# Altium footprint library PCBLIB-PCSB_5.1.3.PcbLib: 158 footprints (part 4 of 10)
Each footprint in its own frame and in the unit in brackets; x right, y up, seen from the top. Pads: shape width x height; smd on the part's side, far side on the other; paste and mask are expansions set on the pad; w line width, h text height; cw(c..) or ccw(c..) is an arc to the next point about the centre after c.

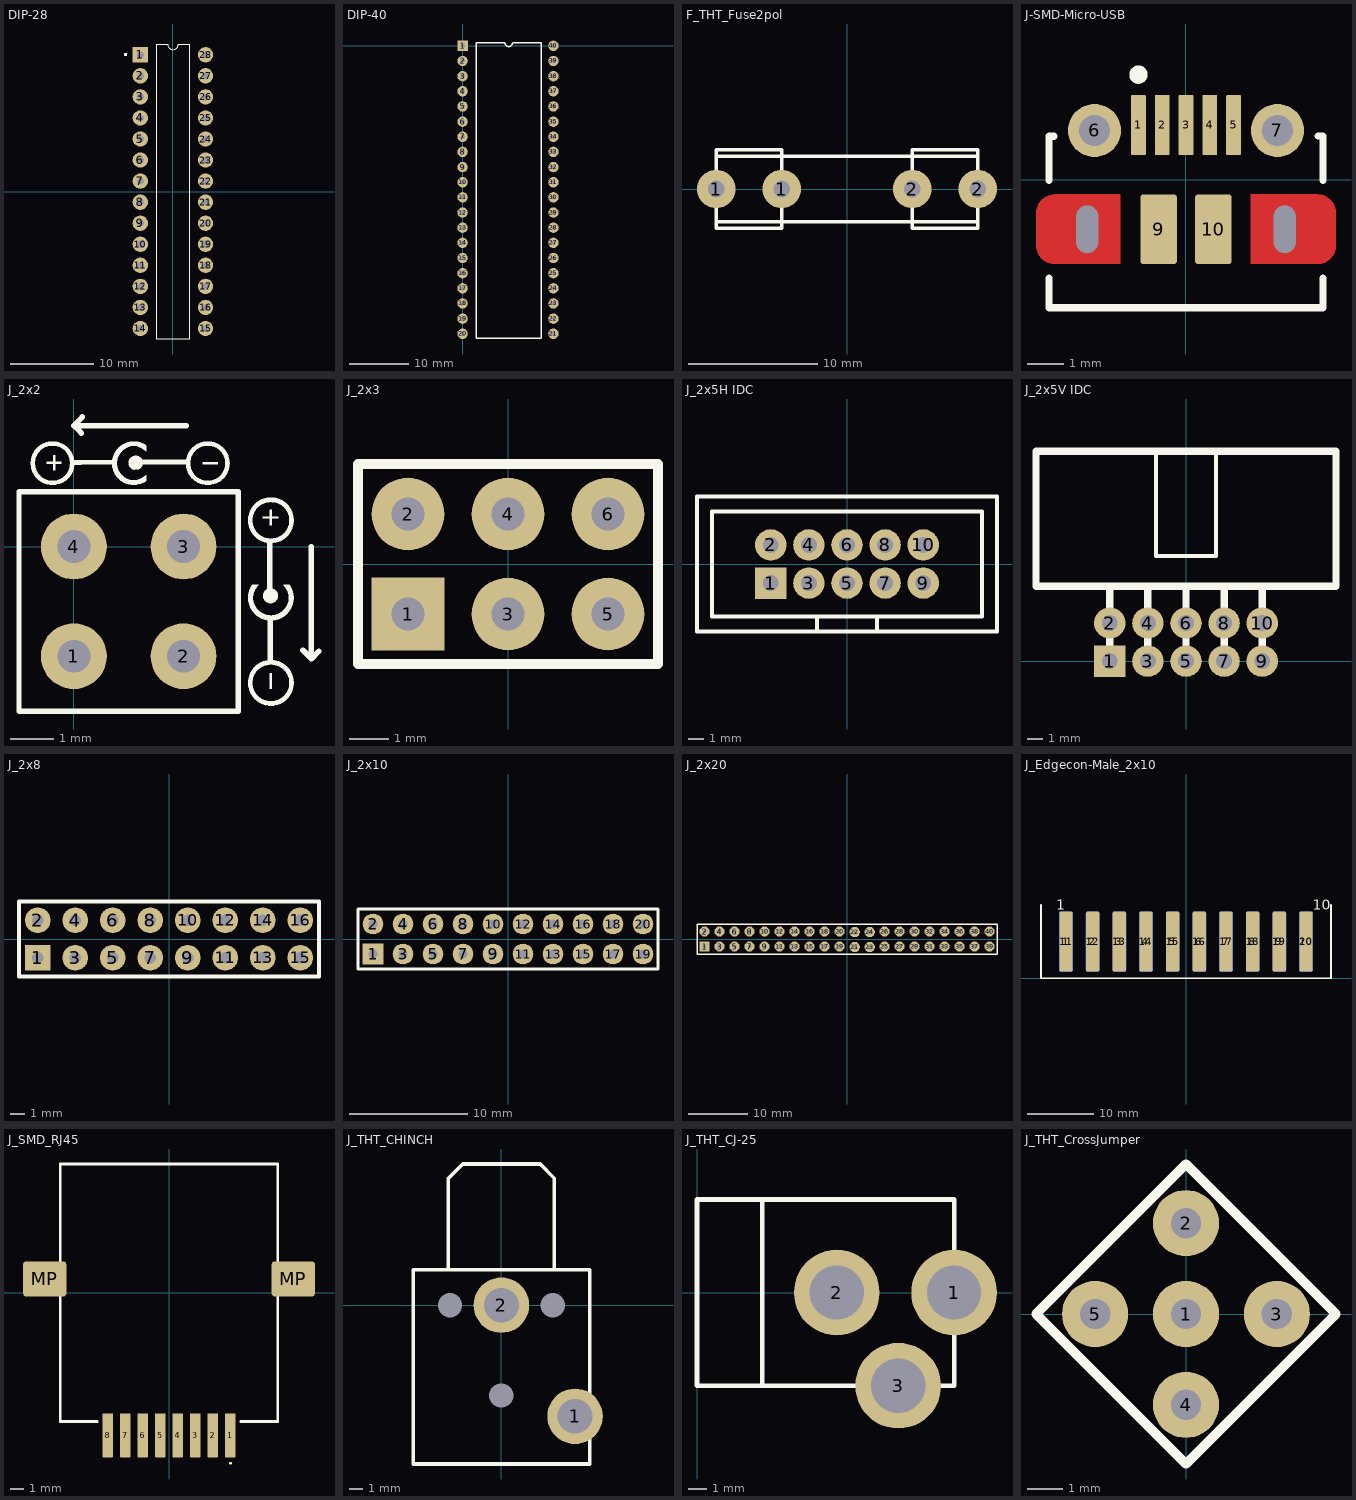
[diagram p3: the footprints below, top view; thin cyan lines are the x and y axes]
## DIP-28 [mm] "LB-2024-04-17"
pads (28):
  rect 1.85x1.85 hole 0.85: 1(-3.935,16.51)
  round 1.85 hole 0.85: 2(-3.935,13.97) 3(-3.935,11.43) 4(-3.935,8.89) 5(-3.935,6.35) 6(-3.935,3.81) 7(-3.935,1.27) 8(-3.935,-1.27) 9(-3.935,-3.81) 10(-3.935,-6.35) 11(-3.935,-8.89) 12(-3.935,-11.43) 13(-3.935,-13.97) 14(-3.935,-16.51) 15(3.935,-16.51) 16(3.935,-13.97) 17(3.935,-11.43) 18(3.935,-8.89) 19(3.935,-6.35) 20(3.935,-3.81) 21(3.935,-1.27) 22(3.935,1.27) 23(3.935,3.81) 24(3.935,6.35) 25(3.935,8.89) 26(3.935,11.43) 27(3.935,13.97) 28(3.935,16.51)
Top Overlay:
  circle w0.2: c-5.714,16.544 r0.1
  lines w0.14: -0.66,17.78 -1,17.78 -2,17.78 -2,-17.78 2,-17.78 2,17.78 ; -0.635,17.78 ccw(c0,17.78) 0.635,17.78 ; 0.642,17.78 1.642,17.78 1.981,17.78
Mechanical 13:
  circle w0.2: c-5.714,16.544 r0.1

## DIP-40 [mm] "LB-2024-04-17"
pads (40):
  rect 1.75x1.75 hole 0.75: 1(0,0)
  round 1.75 hole 0.75: 2(0,-2.54) 3(0,-5.08) 4(0,-7.62) 5(0,-10.16) 6(0,-12.7) 7(0,-15.24) 8(0,-17.78) 9(0,-20.32) 10(0,-22.86) 11(0,-25.4) 12(0,-27.94) 13(0,-30.48) 14(0,-33.02) 15(0,-35.56) 16(0,-38.1) 17(0,-40.64) 18(0,-43.18) 19(0,-45.72) 20(0,-48.26) 21(15.24,-48.26) 22(15.24,-45.72) 23(15.24,-43.18) 24(15.24,-40.64) 25(15.24,-38.1) 26(15.24,-35.56) 27(15.24,-33.02) 28(15.24,-30.48) 29(15.24,-27.94) 30(15.24,-25.4) 31(15.24,-22.86) 32(15.24,-20.32) 33(15.24,-17.78) 34(15.24,-15.24) 35(15.24,-12.7) 36(15.24,-10.16) 37(15.24,-7.62) 38(15.24,-5.08) 39(15.24,-2.54) 40(15.24,0)
Top Overlay:
  lines w0.254: 2.286,-49.022 13.208,-49.022 13.208,0.508 8.382,0.508 cw(c7.747,0.508) 7.112,0.508 2.286,0.508 2.286,-49.022

## F_THT_Fuse2pol [mm] "LB-2024-04-17"
pads (4):
  round 3 hole 1.3: 1(-10.163,0.008) 1(-5.083,0.008) 2(5.077,0.008) 2(10.157,0.008)
Top Overlay:
  lines w0.254: -10.163,-2.532 -10.163,-3.04 -5.083,-3.04 -5.083,-2.532 -5.083,2.548 -5.083,3.056 -10.163,3.056 -10.163,2.548 ; -10.163,-2.532 10.157,-2.532 ; -10.163,-2.532 -10.163,2.548 ; -10.163,2.548 10.157,2.548 ; 10.157,-2.532 10.157,-3.04 5.077,-3.04 5.077,-2.532 5.077,2.548 5.077,3.056 10.157,3.056 10.157,2.548 ; 10.157,-2.532 10.157,2.548

## J-SMD-Micro-USB [mm] "LB-2024-04-18"
height 2.673
pads (11):
  rrect15% 0.4x1.65 smd paste-0.02 mask+0.05: 1(-1.3,1.5) 2(-0.65,1.5) 3(0,1.5) 4(0.65,1.5) 5(1.3,1.5)
  round 1.45 hole 0.85: 6(-2.5,1.35) 7(2.5,1.35)
  rrect50% 0x0 hole 0.6 slot 1.3 at 90 deg: 8(-2.7,-1.35) 11(2.7,-1.35)
  rrect15% 1x1.9 smd paste-0.02 mask+0.05: 9(-0.75,-1.35) 10(0.75,-1.35)
Top Layer:
  circle w0.5: c-3.6,-1.8 r0.25
  circle w0.5: c-3.6,-0.9 r0.25
  circle w0.5: c3.6,-1.8 r0.25
  circle w0.5: c3.6,-0.9 r0.25
  region: -1.8,-2.3 -1.8,-0.4 -3.6,-0.4 -3.6,-2.3
  region: -3.6,-1.8 -3.6,-0.9 -4.1,-0.9 -4.1,-1.8
  region: 1.775,-0.4 1.775,-2.3 3.6,-2.3 3.6,-0.4
  region: 3.6,-0.9 3.6,-1.8 4.1,-1.8 4.1,-0.9
Top Overlay:
  circle w0.25: c-1.3,2.875 r0.125
  lines w0.2: -3.745,-2.688 -3.745,-3.5 3.745,-3.5 3.745,-2.688 ; -3.745,-0.012 -3.745,1.195 -3.614,1.195 ; 3.615,1.2 3.745,1.2 3.745,-0.012

## J_2x2 [mil] "LB-2024-05-28"
pads (4):
  round 60 hole 30: 1(0,-100) 2(100,-100) 3(100,0) 4(0,0)
Top Overlay:
  drawing of 20 lines, arcs and shapes, not listed

## J_2x3 [mm] "LB-2024-04-19"
pads (6):
  rect 1.85x1.85 hole 0.85 mask+0.102: 1(-2.54,-1.27)
  round 1.85 hole 0.85 mask+0.102: 2(-2.54,1.27) 3(0,-1.27) 4(0,1.27) 5(2.54,-1.27) 6(2.54,1.27)
Top Overlay:
  lines w0.254: -3.81,-2.54 -3.81,2.54 3.81,2.54 3.81,-2.54 -3.81,-2.54

## J_2x5H IDC [mm] "LB-2024-04-19"
height 9
pads (10):
  rect 2.1x2.1 hole 1.05 mask+0.102: 1(-5.08,-1.27)
  round 2.1 hole 1.05 mask+0.102: 2(-5.08,1.27) 3(-2.54,-1.27) 4(-2.54,1.27) 5(0,-1.27) 6(0,1.27) 7(2.54,-1.27) 8(2.54,1.27) 9(5.08,-1.27) 10(5.08,1.27)
Top Overlay:
  lines w0.254: -2,-4.5 -2,-3.5 ; -0.5,4.5 10,4.5 10,-4.5 -10,-4.5 -10,4.5 0,4.5 ; 2,-4.5 2,-3.5 ; -9,-3.5 -9,3.5 9,3.5 9,-3.5 -9,-3.5

## J_2x5V IDC [mm] "LB-2024-04-19"
height 9
pads (10):
  rect 2.1x2.1 hole 1.05 mask+0.102: 1(-5.08,0)
  round 2.1 hole 1.05 mask+0.102: 2(-5.08,2.54) 3(-2.54,0) 4(-2.54,2.54) 5(0,0) 6(0,2.54) 7(2.54,0) 8(2.54,2.54) 9(5.08,0) 10(5.08,2.54)
Top Overlay:
  lines w0.254: -2,14 -2,7 2,7 2,14
  lines w0.5: -5.08,0 -5.08,5 ; -2.54,0 -2.54,5 ; 0,0 0,5 ; 2.54,0 2.54,5 ; 5.08,0 5.08,5 ; 0,5 -10,5 -10,14 10,14 10,5 0,5

## J_2x8 [mm] "LB-2024-04-19"
pads (16):
  rect 1.75x1.75 hole 0.75: 1(-8.89,-1.27)
  round 1.75 hole 0.75: 2(-8.89,1.27) 3(-6.35,-1.27) 4(-6.35,1.27) 5(-3.81,-1.27) 6(-3.81,1.27) 7(-1.27,-1.27) 8(-1.27,1.27) 9(1.27,-1.27) 10(1.27,1.27) 11(3.81,-1.27) 12(3.81,1.27) 13(6.35,-1.27) 14(6.35,1.27) 15(8.89,-1.27) 16(8.89,1.27)
Top Overlay:
  lines w0.254: -10.16,-2.54 -10.16,2.54 10.16,2.54 10.16,-2.54 -10.16,-2.54

## J_2x10 [mm] "LB-2024-4-19"
pads (20):
  rect 1.75x1.75 hole 0.75: 1(-11.43,-1.27)
  round 1.75 hole 0.75: 2(-11.43,1.27) 3(-8.89,-1.27) 4(-8.89,1.27) 5(-6.35,-1.27) 6(-6.35,1.27) 7(-3.81,-1.27) 8(-3.81,1.27) 9(-1.27,-1.27) 10(-1.27,1.27) 11(1.27,-1.27) 12(1.27,1.27) 13(3.81,-1.27) 14(3.81,1.27) 15(6.35,-1.27) 16(6.35,1.27) 17(8.89,-1.27) 18(8.89,1.27) 19(11.43,-1.27) 20(11.43,1.27)
Top Overlay:
  lines w0.254: -12.7,-2.54 -12.7,2.54 12.7,2.54 12.7,-2.54 -12.7,-2.54

## J_2x20 [mm] "LB-2024-4-19"
pads (40):
  rect 1.75x1.75 hole 0.75: 1(-24.13,-1.224)
  round 1.75 hole 0.75: 2(-24.13,1.316) 3(-21.59,-1.224) 4(-21.59,1.316) 5(-19.05,-1.224) 6(-19.05,1.316) 7(-16.51,-1.224) 8(-16.51,1.316) 9(-13.97,-1.224) 10(-13.97,1.316) 11(-11.43,-1.224) 12(-11.43,1.316) 13(-8.89,-1.224) 14(-8.89,1.316) 15(-6.35,-1.224) 16(-6.35,1.316) 17(-3.81,-1.224) 18(-3.81,1.316) 19(-1.27,-1.224) 20(-1.27,1.316) 21(1.296,-1.316) 22(1.296,1.224) 23(3.836,-1.316) 24(3.836,1.224) 25(6.35,-1.224) 26(6.35,1.316) 27(8.89,-1.224) 28(8.89,1.316) 29(11.43,-1.224) 30(11.43,1.316) 31(13.97,-1.224) 32(13.97,1.316) 33(16.51,-1.224) 34(16.51,1.316) 35(19.05,-1.224) 36(19.05,1.316) 37(21.59,-1.224) 38(21.59,1.316) 39(24.13,-1.224) 40(24.13,1.316)
Top Overlay:
  lines w0.254: -25.4,-2.494 25.4,-2.494 25.4,2.586 -25.4,2.586 -25.4,-2.494

## J_Edgecon-Male_2x10 [mm] "PS-2024-06-15"
pads (20):
  rrect25% 2x9 smd paste-0.02 mask+0.05: 1(-18,5.5) 2(-14,5.5) 3(-10,5.5) 4(-6,5.5) 5(-2,5.5) 6(2,5.5) 7(6,5.5) 8(10,5.5) 9(14,5.5) 10(18,5.5)
  rrect25% 2x9 smd far side paste-0.02 mask+0.05: 11(-18,5.5) 12(-14,5.5) 13(-10,5.5) 14(-6,5.5) 15(-2,5.5) 16(2,5.5) 17(6,5.5) 18(10,5.5) 19(14,5.5) 20(18,5.5)
Bottom Layer:
  lines w0.254: -18,8.75 -18,9
Top Overlay:
  lines w0.254: -21.75,11 -21.75,10.75 -21.75,0 0,0 21.75,0 21.75,11
  text "10" at 19.004,10.254 h1.52
  text "1" at -19.496,10.254 h1.52
Bottom Overlay:
  text "20" at 21.496,10.254 h1.52
  text "11" at -18.754,10.254 h1.52

## J_SMD_RJ45 [mm] "LB-2024-05-31"
pads (10):
  rrect15% 0.76x3.185 smd paste-0.02 mask+0.05: 1(4.445,-10.325) 2(3.175,-10.325) 3(1.905,-10.325) 4(0.635,-10.325) 5(-0.635,-10.325) 6(-1.905,-10.325) 7(-3.175,-10.325) 8(-4.445,-10.325)
  rrect15% 3.12x2.54 smd paste-0.02 mask+0.05: MP(-9,1) MP(9,1)
Top Overlay:
  lines w0.1: 4.445,-12.4 cw(c4.445,-12.35) 4.445,-12.3 cw(c4.445,-12.35) 4.445,-12.4
  lines w0.2: -5.2,-9.325 -7.87,-9.325 -7.87,2.6 -7.87,5.8 -7.87,9.325 7.87,9.325 7.87,2.6 7.87,-9.325 5.2,-9.325

## J_THT_CHINCH [mm] "LB-2024-04-19"
pads (5):
  round 4 hole 2.5: 1(5.3,-8) 2(0,0)
  round 0.5 hole 1.75: 3(-3.7,0) 3(0,-6.5) 3(3.7,0)
Top Overlay:
  lines w0.254: -3.81,2.54 -3.81,9.144 -2.794,10.16 2.794,10.16 3.81,9.144 3.81,2.54 ; -6.35,-11.43 -6.35,2.54 -5.08,2.54 5.08,2.54 6.35,2.54 6.35,-11.43 -6.35,-11.43

## J_THT_CJ-25 [mm] "LB-2024-04-19"
height 1.7
pads (3):
  round 4.6 hole 2.9: 1(13.8,0) 2(7.5,0) 3(10.8,-5)
Top Overlay:
  lines w0.254: 3.5,-5 3.5,5 ; 0,-5 0,5 13.8,5 13.8,-5 0,-5

## J_THT_CrossJumper [mm] "LB-2024-04-19"
pads (5):
  round 1.85 hole 0.85: 1(0,0) 2(0,2.54) 3(2.54,0) 4(0,-2.54) 5(-2.54,0)
Top Overlay:
  lines w0.254: -4.191,0 0,-4.191 4.191,0 0,4.191 -4.191,0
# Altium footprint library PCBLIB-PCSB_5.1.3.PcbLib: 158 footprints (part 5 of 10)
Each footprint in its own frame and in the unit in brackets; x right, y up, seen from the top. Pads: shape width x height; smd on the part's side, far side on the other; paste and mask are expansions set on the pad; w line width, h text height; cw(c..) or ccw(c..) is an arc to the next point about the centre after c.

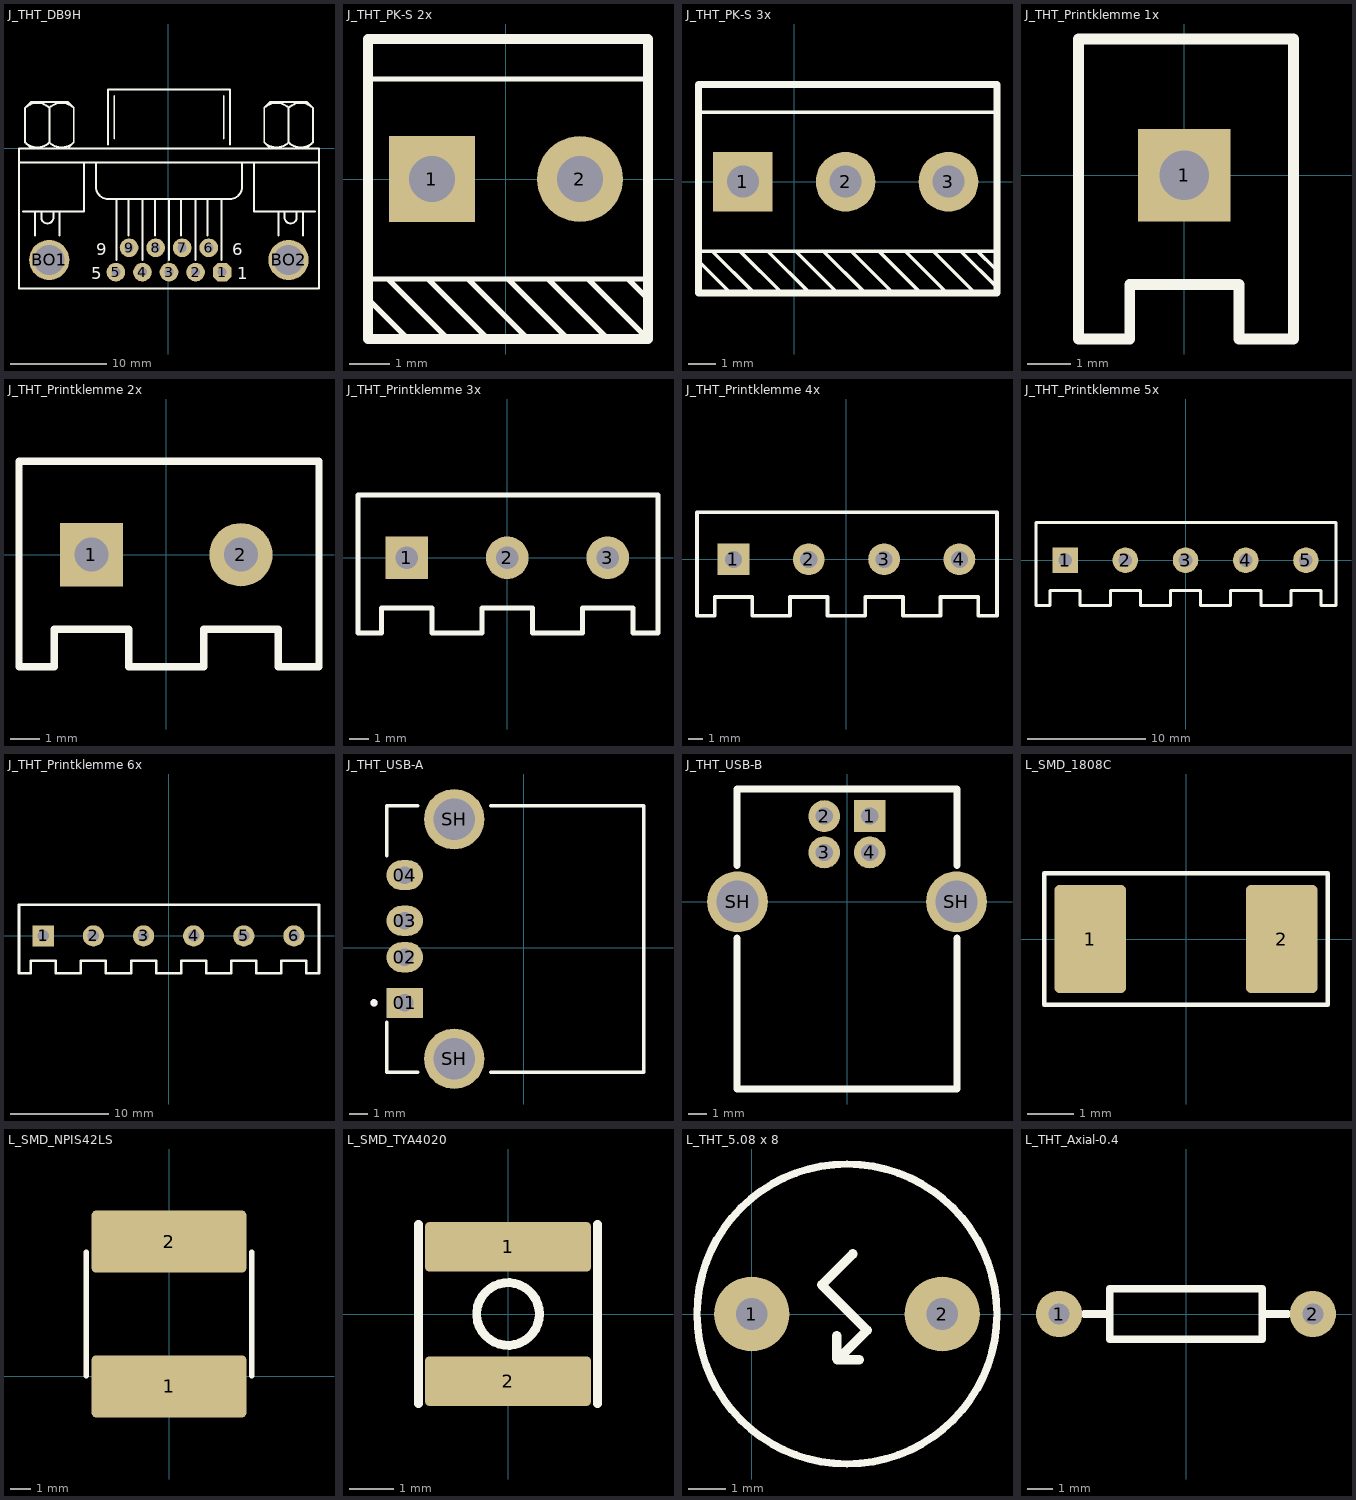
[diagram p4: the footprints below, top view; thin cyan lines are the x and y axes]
## J_THT_DB9H [mm] "LB-2024-04-17"
pads (11):
  oct 1.95x1.95 hole 0.95: 1(5.6,-12.937)
  round 1.95 hole 0.95: 2(2.827,-12.937) 3(0.054,-12.937) 4(-2.718,-12.937) 5(-5.491,-12.937) 6(4.203,-10.397) 7(1.43,-10.397) 8(-1.343,-10.397) 9(-4.115,-10.397)
  round 4.2 hole 3.15: BO1(-12.455,-11.667) BO2(12.543,-11.667)
Top Overlay:
  lines w0.203: -15.609,-1.507 15.718,-1.507 ; -15.186,-6.587 -8.836,-6.587 -8.836,-1.507 ; -14.976,0.608 ccw(c-13.704,1.88) -12.432,0.608 ; -14.976,4.211 cw(c-13.704,2.938) -12.432,4.211 ; -14.339,-0.025 -14.974,0.61 -14.974,4.208 -14.339,4.843 -10.529,4.843 -9.894,4.208 -9.894,0.61 -10.529,-0.025 ; -13.916,-9.127 -13.916,-6.587 ; -13.281,-6.587 -13.281,-7.222 ccw(c-12.646,-7.222) -12.011,-7.222 -12.011,-6.587 ; -12.436,0.608 ccw(c-11.164,1.88) -9.892,0.608 ; -12.436,4.211 cw(c-11.164,2.938) -9.892,4.211 ; -12.434,0.61 -12.434,4.208 ; -11.376,-9.127 -11.376,-6.587 ; -7.566,-1.507 -7.566,-4.047 ccw(c-6.296,-4.047) -6.296,-5.317 6.404,-5.317 ccw(c6.404,-4.047) 7.674,-4.047 7.674,-1.507 ; -6.296,0.398 -6.296,6.113 6.404,6.113 6.404,0.398 ; -5.661,1.033 -5.661,5.478 ; -5.449,-11.667 -5.449,-5.317 ; -4.179,-9.127 -4.179,-5.317 ; -2.697,-11.667 -2.697,-5.317 ; -1.427,-9.127 -1.427,-5.317 ; 0.054,-11.667 0.054,-5.317 ; 1.324,-9.127 1.324,-5.317 ; 2.806,-11.667 2.806,-5.317 ; 4.076,-9.127 4.076,-8.915 4.076,-5.317 ; 5.558,-11.667 5.558,-5.317 ; 5.769,1.033 5.769,5.478 ; 8.944,-1.507 8.944,-6.587 15.294,-6.587 ; 10,0.608 ccw(c11.273,1.88) 12.545,0.608 ; 10,4.211 cw(c11.273,2.938) 12.545,4.211 ; 10.638,-0.025 10.003,0.61 10.003,4.208 10.638,4.843 14.448,4.843 15.083,4.208 15.083,0.61 14.448,-0.025 ; 11.484,-9.127 11.484,-6.587 ; 12.119,-6.587 12.119,-7.222 ccw(c12.754,-7.222) 13.389,-7.222 13.389,-6.587 ; 12.54,0.608 ccw(c13.813,1.88) 15.085,0.608 ; 12.54,4.211 cw(c13.813,2.938) 15.085,4.211 ; 12.543,0.61 12.543,4.208 ; 14.024,-9.127 14.024,-6.587 ; -15.609,-14.63 -15.609,-0.025 15.718,-0.025 15.718,-14.63 -15.609,-14.63
  text "9" at -7.566,-11.159 h1.27
  text "5" at -8.074,-13.699 h1.27
  text "1" at 7.166,-13.699 h1.27
  text "6" at 6.658,-11.159 h1.27

## J_THT_PK-S 2x [mm] "LB-2024-05-03g"
pads (2):
  rect 2.15x2.15 hole 1.15: 1(-1.85,0)
  round 2.15 hole 1.15: 2(1.85,0)
Top Overlay:
  lines w0.127: -3.45,2.5 3.55,2.5 ; -2.45,-4 -3.45,-3 -3.45,-2.5 3.55,-2.5 ; -1.95,-2.5 -0.45,-4 ; -1.45,-4 -2.95,-2.5 ; -0.95,-2.5 0.55,-4 ; 0.05,-2.5 1.55,-4 ; 1.05,-2.5 2.55,-4 ; 3.55,-4 2.05,-2.5 ; 3.55,-3 3.05,-2.5 ; -2.95,-2.5 -2.95,-2.5 ; 2.05,-2.5 2.05,-2.5 ; 3.05,-2.5 3.05,-2.5 ; 3.05,-2.5 3.05,-2.5
  lines w0.254: -3.45,-4 -2.91,-4 3.55,-4 3.55,3.5 -3.45,3.5 -3.45,2.365 -3.45,-4

## J_THT_PK-S 3x [mm] "LB-2024-05-03g"
pads (3):
  rect 2.15x2.15 hole 1.15: 1(-1.85,0)
  round 2.15 hole 1.15: 2(1.85,0) 3(5.55,0)
Top Overlay:
  lines w0.127: -3.5,-2.5 6.5,-2.5 7.3,-2.5 ; -3.45,2.5 7.3,2.5 ; -3.4,-2.9 -2.3,-4 ; -1.95,-2.5 -0.45,-4 ; -1.45,-4 -2.95,-2.5 ; -0.95,-2.5 0.55,-4 ; 0.05,-2.5 1.55,-4 ; 1.05,-2.5 2.55,-4 ; 3.55,-4 2.05,-2.5 ; 4,-2.5 5.425,-3.925 ; 4.575,-4.025 3.05,-2.5 ; 5,-2.5 6.5,-4 ; 6,-2.5 7.3,-3.8 ; 7,-2.5 6.6,-2.5 7.25,-3.15 ; -2.95,-2.5 -2.95,-2.5 ; 2.05,-2.5 2.05,-2.5 ; 3.05,-2.5 3.05,-2.5 ; 3.05,-2.5 3.05,-2.5
  lines w0.254: -3.45,-4 -2.91,-4 3.55,-4 7.3,-4 7.3,3.5 -3.45,3.5 -3.45,2.365 -3.45,-4

## J_THT_Printklemme 1x [mm] "LB-2024-04-17"
pads (1):
  rect 2.15x2.15 hole 1.15: 1(0,0)
Top Overlay:
  lines w0.254: -2.46,-3.81 -1.27,-3.81 -1.27,-2.54 1.27,-2.54 1.27,-3.81 2.54,-3.81 2.54,3.175 -2.46,3.175 -2.46,2.365 -2.46,-3.81

## J_THT_Printklemme 2x [mm] "LB-2024-04-17"
pads (2):
  rect 2.15x2.15 hole 1.15: 1(-2.54,0)
  round 2.15 hole 1.15: 2(2.54,0)
Top Overlay:
  lines w0.254: 1.27,-3.81 1.27,-2.54 ; 1.27,-3.81 -1.27,-3.81 -1.27,-2.54 -3.81,-2.54 -3.81,-3.81 -5,-3.81 -5,2.365 -5,3.175 5.19,3.175 5.19,-3.81 3.81,-3.81 ; 1.27,-3.81 1.27,-2.54 ; 1.27,-2.54 3.81,-2.54 ; 3.81,-3.81 3.81,-2.54 ; 3.81,-3.81 3.81,-2.54

## J_THT_Printklemme 3x [mm] "LB-2024-04-17"
pads (3):
  rect 2.15x2.15 hole 1.15: 1(-5.08,0)
  round 2.15 hole 1.15: 2(0,0) 3(5.08,0)
Top Overlay:
  lines w0.254: -1.27,-3.81 -1.27,-2.54 ; -1.27,-3.81 -3.81,-3.81 -3.81,-2.54 -6.35,-2.54 -6.35,-3.81 -7.54,-3.81 -7.54,2.365 -7.54,3.175 2.65,3.175 7.62,3.175 7.62,-3.81 6.35,-3.81 6.35,-2.54 3.81,-2.54 3.81,-3.81 1.27,-3.81 ; -1.27,-3.81 -1.27,-2.54 ; -1.27,-2.54 1.27,-2.54 ; 1.27,-3.81 1.27,-2.54 ; 1.27,-3.81 1.27,-2.54

## J_THT_Printklemme 4x [mm] "LB-2024-04-17"
pads (4):
  rect 2.15x2.15 hole 1.15: 1(-7.62,0)
  round 2.15 hole 1.15: 2(-2.54,0) 3(2.54,0) 4(7.62,0)
Top Overlay:
  lines w0.254: -3.81,-3.81 -3.81,-2.54 ; -3.81,-3.81 -6.35,-3.81 -6.35,-2.54 -8.89,-2.54 -8.89,-3.81 -10.08,-3.81 -10.08,2.365 -10.08,3.175 0.11,3.175 10.16,3.175 10.16,-3.81 8.89,-3.81 8.89,-2.54 6.35,-2.54 6.35,-3.81 3.81,-3.81 3.81,-2.54 1.27,-2.54 1.27,-3.81 -1.27,-3.81 ; -3.81,-3.81 -3.81,-2.54 ; -3.81,-2.54 -1.27,-2.54 ; -1.27,-3.81 -1.27,-2.54 ; -1.27,-3.81 -1.27,-2.54

## J_THT_Printklemme 5x [mm] "LB-2024-04-17"
pads (5):
  rect 2.15x2.15 hole 1.15: 1(-10.16,0)
  round 2.15 hole 1.15: 2(-5.08,0) 3(0,0) 4(5.08,0) 5(10.16,0)
Top Overlay:
  lines w0.254: -6.35,-3.81 -6.35,-2.54 ; -6.35,-3.81 -8.89,-3.81 -8.89,-2.54 -11.43,-2.54 -11.43,-3.81 -12.62,-3.81 -12.62,2.365 -12.62,3.175 -2.43,3.175 12.7,3.175 12.7,-3.81 11.43,-3.81 11.43,-2.54 8.89,-2.54 8.89,-3.81 6.35,-3.81 6.35,-2.54 3.81,-2.54 3.81,-3.81 1.27,-3.81 1.27,-2.54 -1.27,-2.54 -1.27,-3.81 -3.81,-3.81 ; -6.35,-3.81 -6.35,-2.54 ; -6.35,-2.54 -3.81,-2.54 ; -3.81,-3.81 -3.81,-2.54 ; -3.81,-3.81 -3.81,-2.54

## J_THT_Printklemme 6x [mm] "LB-2024-04-17"
pads (6):
  rect 2.15x2.15 hole 1.15: 1(-12.7,0)
  round 2.15 hole 1.15: 2(-7.62,0) 3(-2.54,0) 4(2.54,0) 5(7.62,0) 6(12.7,0)
Top Overlay:
  lines w0.254: -8.89,-3.81 -8.89,-2.54 ; -8.89,-3.81 -11.43,-3.81 -11.43,-2.54 -13.97,-2.54 -13.97,-3.81 -15.16,-3.81 -15.16,2.365 -15.16,3.175 -4.97,3.175 15.24,3.175 15.24,-3.81 13.97,-3.81 13.97,-2.54 11.43,-2.54 11.43,-3.81 8.89,-3.81 8.89,-2.54 6.35,-2.54 6.35,-3.81 3.81,-3.81 3.81,-2.54 1.27,-2.54 1.27,-3.81 -1.27,-3.81 -1.27,-2.54 -3.81,-2.54 -3.81,-3.81 -6.35,-3.81 ; -8.89,-3.81 -8.89,-2.54 ; -8.89,-2.54 -6.35,-2.54 ; -6.35,-3.81 -6.35,-2.54 ; -6.35,-3.81 -6.35,-2.54

## J_THT_USB-A [mm] "LB-2024-04-29"
pads (6):
  rect 2x1.65 hole 0.95: 01(-6.536,-3.032)
  oval 2x1.65 hole 0.95: 02(-6.536,-0.532) 03(-6.536,1.468) 04(-6.536,3.968)
  round 3.316 hole 2.3: SH(-3.826,-6.102) SH(-3.826,7.038)
Top Overlay:
  circle w0.2: c-8.226,-3.032 r0.1
  lines w0.2: -7.526,-4.097 -7.526,-6.832 -5.836,-6.832 ; -7.526,5.033 -7.526,7.768 -5.836,7.768 ; -1.816,-6.832 6.574,-6.832 6.574,7.768 -1.816,7.768
Mechanical 13:
  circle w0.2: c-8.226,-3.032 r0.1

## J_THT_USB-B [mm] "LB-2024-04-15"
pads (6):
  rect 1.75x1.75 hole 0.95: 1(1.25,4.71)
  round 1.75 hole 0.95: 2(-1.25,4.71) 3(-1.25,2.71) 4(1.25,2.71)
  round 3.346 hole 2.33: SH(-6.02,0) SH(6.02,0)
Top Overlay:
  lines w0.4: -6.05,-2 -6.05,-10.3 6.05,-10.3 6.05,-2 ; -6.05,2 -6.05,6.2 6.05,6.2 6.05,2

## L_SMD_1808C [mm] "LB-2024-04-17"
height 2
pads (2):
  rrect15% 1.55x2.35 smd paste-0.02 mask+0.05: 1(-2.075,0) 2(2.075,0)
Top Overlay:
  lines w0.1: -3.075,-1.425 -3.075,1.425 3.075,1.425 3.075,-1.425 -3.075,-1.425

## L_SMD_NPIS42LS [mm] "LB-2024-04-17"
pads (2):
  rrect15% 7.5x3 smd paste-0.02 mask+0.05: 1(0,-0.5) 2(0,6.5)
Top Overlay:
  lines w0.254: -4,0 -4,3 -4,6 ; 4,0 4,3 4,6

## L_SMD_TYA4020 [mm] "LB-2024-04-25"
height 2.1
pads (2):
  rrect15% 3.7x1.1 smd paste-0.02 mask+0.05: 1(0,1.5) 2(0,-1.5)
Top Overlay:
  circle w0.2: c0,0 r0.7
  lines w0.2: -2,-2 -2,0 -2,2 ; 2,-2 2,0 2,2

## L_THT_5.08 x 8 [mm] "LB-2024-04-17"
pads (2):
  round 2 hole 0.85: 1(0,0) 2(5.08,0)
Top Overlay:
  circle w0.2: c2.54,0 r4
  lines w0.254: 2.261,-0.762 2.261,-1.194 ; 2.261,-0.584 2.261,-1.194 ; 2.692,1.6 1.867,0.775 3.073,-0.432 2.286,-1.219 ; 2.261,-1.194 2.286,-1.219 ; 2.286,-1.219 2.87,-1.219 ; 2.286,-1.219 2.87,-1.219 ; 2.286,-1.219 2.87,-1.219

## L_THT_Axial-0.4 [mm]
pads (2):
  round 1.85 hole 0.85: 1(-5.08,0) 2(5.08,0)
Top Overlay:
  lines w0.305: -4.064,0 -3.048,0 ; 3.048,0 4.064,0 ; -3.048,-1.016 3.048,-1.016 3.048,1.016 -3.048,1.016 -3.048,-1.016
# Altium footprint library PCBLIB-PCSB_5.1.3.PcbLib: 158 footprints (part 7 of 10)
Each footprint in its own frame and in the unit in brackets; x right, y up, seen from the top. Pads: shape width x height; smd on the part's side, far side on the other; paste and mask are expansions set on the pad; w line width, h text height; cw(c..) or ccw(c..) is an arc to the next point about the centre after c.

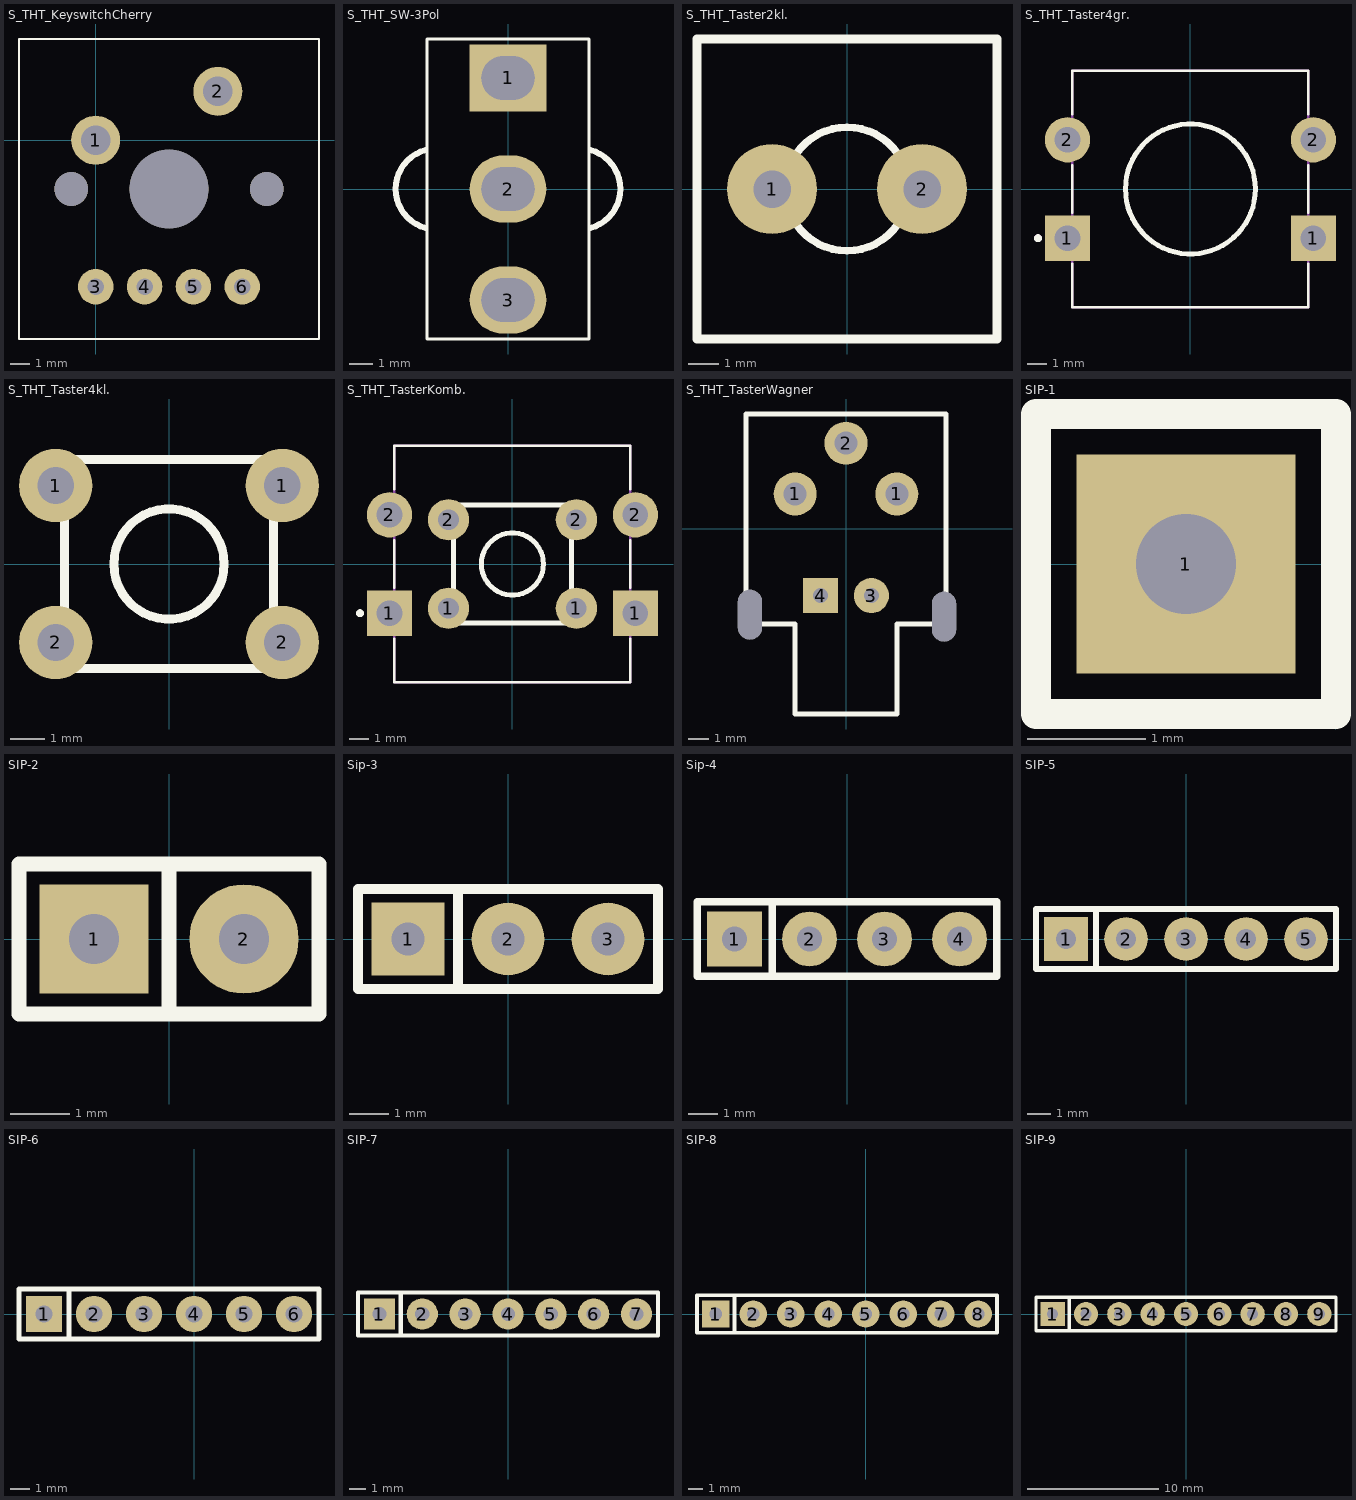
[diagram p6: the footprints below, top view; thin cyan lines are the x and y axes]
## S_THT_KeyswitchCherry [mm] "LB-2024-04-18"
pads (9):
  round 2.55 hole 1.55: 1(0,0) 2(6.35,2.54)
  round 1.85 hole 0.85: 3(0,-7.62) 4(2.54,-7.62) 5(5.08,-7.62) 6(7.62,-7.62)
  round 1.753 hole 1.753 unplated: ""(-1.27,-2.54) ""(8.89,-2.54)
  round 4.089 hole 4.089 unplated: ""(3.81,-2.54)
Top Overlay:
  lines w0.127: -3.99,-10.34 11.61,-10.34 11.61,5.26 -3.99,5.26 -3.99,-10.34

## S_THT_SW-3Pol [mm]
pads (3):
  rect 3.25x2.85 hole 1.85 slot 2.25 at 0 deg: 1(0,4.7)
  oval 3.25x2.85 hole 1.85 slot 2.25 at 0 deg: 2(0,0) 3(0,-4.7)
Top Overlay:
  lines w0.127: -1.71,-6.35 -3.43,-6.35 ; -1.71,6.35 -3.43,6.35 ; 1.71,-6.35 3.43,-6.35 ; 1.71,6.35 3.43,6.35 ; -3.43,-6.35 -3.43,6.35 ; -3.43,-6.35 3.43,-6.35 ; -3.43,-6.35 -3.43,6.35 ; -3.43,6.35 3.43,6.35 ; 3.43,-6.35 3.43,6.35 ; 3.43,-6.35 3.43,6.35
  lines w0.254: -3.49,-1.65 cw(c-3.048,0) -3.49,1.65 ; 3.49,-1.65 ccw(c3.048,0) 3.49,1.65

## S_THT_Taster2kl. [mm] "LB-2024-04-17"
height 20
pads (2):
  round 3 hole 1.25 unplated: 1(-2.5,0) 2(2.5,0)
Top Overlay:
  circle w0.254: c0,0 r2.062
  lines w0.3: -5,-5 5,-5 5,5 -5,5 -5,-5

## S_THT_Taster4gr. [mm] "LB-2024-04-17"
height 7.8
pads (4):
  rect 2.3x2.3 hole 1.3: 1(-6.25,-2.5) 1(6.25,-2.5)
  round 2.3 hole 1.3: 2(-6.25,2.5) 2(6.25,2.5)
Top Overlay:
  circle w0.2: c-7.75,-2.5 r0.1
  circle w0.254: c0,0 r3.302
  lines w0.127: -6,-3.788 -6,-6 6,-6 6,-3.788 ; -6,-1.212 -6,1.212 ; -6,3.788 -6,6 6,6 6,3.788 ; 6,-1.212 6,1.212
Mechanical 13:
  circle w0.2: c-7.75,-2.5 r0.1
  lines w0.127: -6,-6 -6,6 6,6 6,-6 -6,-6

## S_THT_Taster4kl. [mm] "LB-2024-04-17"
pads (4):
  round 2.1 hole 1.05: 1(-3.25,2.25) 1(3.25,2.25) 2(-3.25,-2.25) 2(3.25,-2.25)
Top Overlay:
  circle w0.254: c0,0 r1.581
  lines w0.254: -3,-3 3,-3 3,3 -3,3 -3,-3

## S_THT_TasterKomb. [mm] "LB-2024-04-17"
height 7.8
pads (8):
  rect 2.3x2.3 hole 1.3: 1(-6.25,-2.5) 1(6.25,-2.5)
  round 2.1 hole 1.05: 1(-3.25,-2.25) 1(3.25,-2.25) 2(-3.25,2.25) 2(3.25,2.25)
  round 2.3 hole 1.3: 2(-6.25,2.5) 2(6.25,2.5)
Top Overlay:
  circle w0.2: c-7.75,-2.5 r0.1
  circle w0.254: c0,0 r1.581
  lines w0.127: -6,-3.788 -6,-6 6,-6 6,-3.788 ; -6,-1.212 -6,1.212 ; -6,3.788 -6,6 6,6 6,3.788 ; 6,-1.212 6,1.212
  lines w0.254: -3,-3 -3,3 3,3 3,-3 -3,-3
Mechanical 13:
  lines w0.127: -6,-6 -6,6 6,6 6,-6 -6,-6

## S_THT_TasterWagner [mm] "LB-2024-04-17"
pads (7):
  round 2.15 hole 1.15: 1(-2.54,1.73) 1(2.54,1.73) 2(0,4.27)
  round 1.75 hole 0.75: 3(1.27,-3.35)
  rect 1.75x1.75 hole 0.75: 4(-1.27,-3.35)
  round 0.1 hole 1.2 slot 2.5 at 90 deg: H1(-4.8,-4.3) H2(4.9,-4.4)
Top Overlay:
  lines w0.254: -5,-4.77 -2.54,-4.77 -2.54,-9.27 1.065,-9.27 2.54,-9.27 2.54,-4.77 5,-4.77 5,5.73 -5,5.73 -5,-4.77

## SIP-1 [mm] "LB-2024-04-17"
pads (1):
  rect 1.85x1.85 hole 0.85: 1(-1.27,0)
Top Overlay:
  lines w0.254: -2.54,-1.27 -2.54,1.27 0,1.27 0,-1.27 -2.54,-1.27

## SIP-2 [mm] "LB-2024-04-17"
pads (2):
  rect 1.85x1.85 hole 0.85: 1(-1.27,0)
  round 1.85 hole 0.85: 2(1.27,0)
Top Overlay:
  lines w0.254: 0,-1.27 0,1.27 ; -2.54,-1.27 -2.54,1.27 2.54,1.27 2.54,-1.27 -2.54,-1.27

## Sip-3 [mm] "LB-2024-04-17"
pads (3):
  rect 1.85x1.85 hole 0.85: 1(-2.54,0)
  round 1.85 hole 0.85: 2(0,0) 3(2.54,0)
Top Overlay:
  lines w0.254: -1.27,-1.27 -1.27,1.27 ; -3.81,-1.27 -3.81,1.27 3.81,1.27 3.81,-1.27 -3.81,-1.27

## Sip-4 [mm] "LB-2024-04-17"
pads (4):
  rect 1.85x1.85 hole 0.85: 1(-3.81,0)
  round 1.85 hole 0.85: 2(-1.27,0) 3(1.27,0) 4(3.81,0)
Top Overlay:
  lines w0.254: -2.54,-1.27 -2.54,1.27 ; -5.08,-1.27 5.08,-1.27 5.08,1.27 -5.08,1.27 -5.08,-1.27

## SIP-5 [mm] "LB-2024-04-17"
pads (5):
  rect 1.85x1.85 hole 0.85: 1(-5.08,0)
  round 1.85 hole 0.85: 2(-2.54,0) 3(0,0) 4(2.54,0) 5(5.08,0)
Top Overlay:
  lines w0.254: -3.81,-1.27 -3.81,1.27 ; -6.35,-1.27 6.35,-1.27 6.35,1.27 -6.35,1.27 -6.35,-1.27

## SIP-6 [mm] "LB-2024-04-17"
pads (6):
  rect 1.85x1.85 hole 0.85: 1(-7.62,0)
  round 1.85 hole 0.85: 2(-5.08,0) 3(-2.54,0) 4(0,0) 5(2.54,0) 6(5.08,0)
Top Overlay:
  lines w0.254: -6.35,-1.27 -6.35,1.27 ; -8.89,-1.27 -8.89,1.27 6.35,1.27 6.35,-1.27 -8.89,-1.27

## SIP-7 [mm] "LB-2024-04-17"
pads (7):
  rect 1.85x1.85 hole 0.85: 1(-7.62,0)
  round 1.85 hole 0.85: 2(-5.08,0) 3(-2.54,0) 4(0,0) 5(2.54,0) 6(5.08,0) 7(7.62,0)
Top Overlay:
  lines w0.254: -6.35,-1.27 -6.35,1.27 ; -8.89,-1.27 8.89,-1.27 8.89,1.27 -8.89,1.27 -8.89,-1.27

## SIP-8 [mm] "LB-2024-04-17"
pads (8):
  rect 1.85x1.85 hole 0.85: 1(-10.16,0)
  round 1.85 hole 0.85: 2(-7.62,0) 3(-5.08,0) 4(-2.54,0) 5(0,0) 6(2.54,0) 7(5.08,0) 8(7.62,0)
Top Overlay:
  lines w0.254: -8.89,-1.27 -8.89,1.27 ; -11.43,-1.27 -11.43,1.27 8.89,1.27 8.89,-1.27 -11.43,-1.27

## SIP-9 [mm] "LB-2024-04-17"
pads (9):
  rect 1.85x1.85 hole 0.85: 1(-10.16,0)
  round 1.85 hole 0.85: 2(-7.62,0) 3(-5.08,0) 4(-2.54,0) 5(0,0) 6(2.54,0) 7(5.08,0) 8(7.62,0) 9(10.16,0)
Top Overlay:
  lines w0.254: -8.89,-1.27 -8.89,1.27 ; -11.43,-1.27 11.43,-1.27 11.43,1.27 -11.43,1.27 -11.43,-1.27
